VERSION 5.7 ;
  NOWIREEXTENSIONATPIN ON ;
  DIVIDERCHAR "/" ;
  BUSBITCHARS "[]" ;
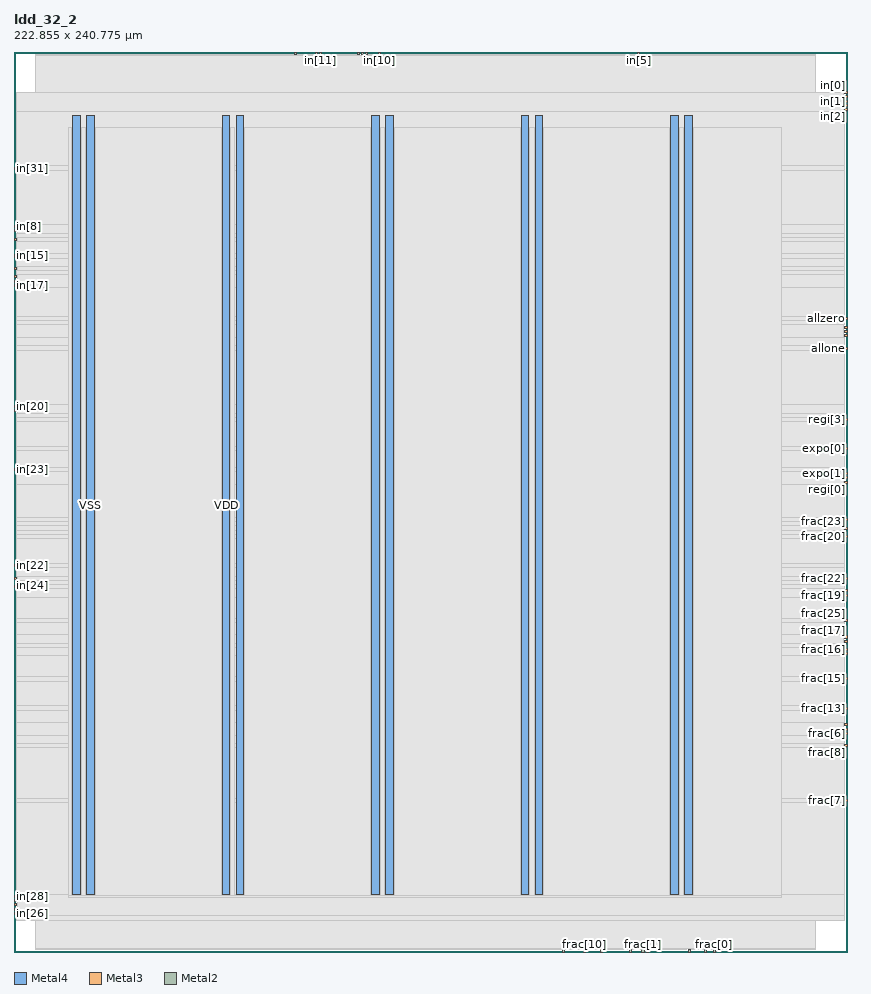
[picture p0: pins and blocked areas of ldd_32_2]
MACRO ldd_32_2
  CLASS BLOCK ;
  FOREIGN ldd_32_2 ;
  ORIGIN 0.000 0.000 ;
  SIZE 222.855 BY 240.775 ;
  PIN VDD
    DIRECTION INOUT ;
    USE POWER ;
    PORT
      LAYER Metal4 ;
        RECT 15.720 15.380 17.720 223.740 ;
    END
    PORT
      LAYER Metal4 ;
        RECT 55.720 15.380 57.720 223.740 ;
    END
    PORT
      LAYER Metal4 ;
        RECT 95.720 15.380 97.720 223.740 ;
    END
    PORT
      LAYER Metal4 ;
        RECT 135.720 15.380 137.720 223.740 ;
    END
    PORT
      LAYER Metal4 ;
        RECT 175.720 15.380 177.720 223.740 ;
    END
  END VDD
  PIN VSS
    DIRECTION INOUT ;
    USE GROUND ;
    PORT
      LAYER Metal4 ;
        RECT 19.420 15.380 21.420 223.740 ;
    END
    PORT
      LAYER Metal4 ;
        RECT 59.420 15.380 61.420 223.740 ;
    END
    PORT
      LAYER Metal4 ;
        RECT 99.420 15.380 101.420 223.740 ;
    END
    PORT
      LAYER Metal4 ;
        RECT 139.420 15.380 141.420 223.740 ;
    END
    PORT
      LAYER Metal4 ;
        RECT 179.420 15.380 181.420 223.740 ;
    END
  END VSS
  PIN allone
    DIRECTION OUTPUT ;
    USE SIGNAL ;
    ANTENNADIFFAREA 1.986000 ;
    PORT
      LAYER Metal3 ;
        RECT 222.295 161.280 222.855 161.840 ;
    END
  END allone
  PIN allzero
    DIRECTION OUTPUT ;
    USE SIGNAL ;
    ANTENNADIFFAREA 1.986000 ;
    PORT
      LAYER Metal3 ;
        RECT 222.295 169.120 222.855 169.680 ;
    END
  END allzero
  PIN expo[0]
    DIRECTION OUTPUT ;
    USE SIGNAL ;
    ANTENNADIFFAREA 1.986000 ;
    PORT
      LAYER Metal3 ;
        RECT 222.295 134.400 222.855 134.960 ;
    END
  END expo[0]
  PIN expo[1]
    DIRECTION OUTPUT ;
    USE SIGNAL ;
    ANTENNADIFFAREA 1.986000 ;
    PORT
      LAYER Metal3 ;
        RECT 222.295 127.680 222.855 128.240 ;
    END
  END expo[1]
  PIN frac[0]
    DIRECTION OUTPUT ;
    USE SIGNAL ;
    ANTENNADIFFAREA 1.986000 ;
    PORT
      LAYER Metal2 ;
        RECT 187.040 0.000 187.600 0.560 ;
    END
  END frac[0]
  PIN frac[10]
    DIRECTION OUTPUT ;
    USE SIGNAL ;
    ANTENNADIFFAREA 1.986000 ;
    PORT
      LAYER Metal2 ;
        RECT 152.320 0.000 152.880 0.560 ;
    END
  END frac[10]
  PIN frac[11]
    DIRECTION OUTPUT ;
    USE SIGNAL ;
    ANTENNADIFFAREA 1.986000 ;
    PORT
      LAYER Metal2 ;
        RECT 146.720 0.000 147.280 0.560 ;
    END
  END frac[11]
  PIN frac[12]
    DIRECTION OUTPUT ;
    USE SIGNAL ;
    ANTENNADIFFAREA 1.986000 ;
    PORT
      LAYER Metal2 ;
        RECT 156.800 0.000 157.360 0.560 ;
    END
  END frac[12]
  PIN frac[13]
    DIRECTION OUTPUT ;
    USE SIGNAL ;
    ANTENNADIFFAREA 1.986000 ;
    PORT
      LAYER Metal3 ;
        RECT 222.295 64.960 222.855 65.520 ;
    END
  END frac[13]
  PIN frac[14]
    DIRECTION OUTPUT ;
    USE SIGNAL ;
    ANTENNADIFFAREA 1.986000 ;
    PORT
      LAYER Metal3 ;
        RECT 222.295 60.480 222.855 61.040 ;
    END
  END frac[14]
  PIN frac[15]
    DIRECTION OUTPUT ;
    USE SIGNAL ;
    ANTENNADIFFAREA 1.986000 ;
    PORT
      LAYER Metal3 ;
        RECT 222.295 72.800 222.855 73.360 ;
    END
  END frac[15]
  PIN frac[16]
    DIRECTION OUTPUT ;
    USE SIGNAL ;
    ANTENNADIFFAREA 1.986000 ;
    PORT
      LAYER Metal3 ;
        RECT 222.295 80.640 222.855 81.200 ;
    END
  END frac[16]
  PIN frac[17]
    DIRECTION OUTPUT ;
    USE SIGNAL ;
    ANTENNADIFFAREA 1.986000 ;
    PORT
      LAYER Metal3 ;
        RECT 222.295 84.000 222.855 84.560 ;
    END
  END frac[17]
  PIN frac[18]
    DIRECTION OUTPUT ;
    USE SIGNAL ;
    ANTENNADIFFAREA 1.986000 ;
    PORT
      LAYER Metal3 ;
        RECT 222.295 79.520 222.855 80.080 ;
    END
  END frac[18]
  PIN frac[19]
    DIRECTION OUTPUT ;
    USE SIGNAL ;
    ANTENNADIFFAREA 1.986000 ;
    PORT
      LAYER Metal3 ;
        RECT 222.295 95.200 222.855 95.760 ;
    END
  END frac[19]
  PIN frac[1]
    DIRECTION OUTPUT ;
    USE SIGNAL ;
    ANTENNADIFFAREA 1.986000 ;
    PORT
      LAYER Metal2 ;
        RECT 168.000 0.000 168.560 0.560 ;
    END
  END frac[1]
  PIN frac[20]
    DIRECTION OUTPUT ;
    USE SIGNAL ;
    ANTENNADIFFAREA 1.986000 ;
    PORT
      LAYER Metal3 ;
        RECT 222.295 110.880 222.855 111.440 ;
    END
  END frac[20]
  PIN frac[21]
    DIRECTION OUTPUT ;
    USE SIGNAL ;
    ANTENNADIFFAREA 1.986000 ;
    PORT
      LAYER Metal3 ;
        RECT 222.295 82.880 222.855 83.440 ;
    END
  END frac[21]
  PIN frac[22]
    DIRECTION OUTPUT ;
    USE SIGNAL ;
    ANTENNADIFFAREA 1.986000 ;
    PORT
      LAYER Metal3 ;
        RECT 222.295 99.680 222.855 100.240 ;
    END
  END frac[22]
  PIN frac[23]
    DIRECTION OUTPUT ;
    USE SIGNAL ;
    ANTENNADIFFAREA 1.986000 ;
    PORT
      LAYER Metal3 ;
        RECT 222.295 113.120 222.855 113.680 ;
    END
  END frac[23]
  PIN frac[24]
    DIRECTION OUTPUT ;
    USE SIGNAL ;
    ANTENNADIFFAREA 1.986000 ;
    PORT
      LAYER Metal3 ;
        RECT 222.295 115.360 222.855 115.920 ;
    END
  END frac[24]
  PIN frac[25]
    DIRECTION OUTPUT ;
    USE SIGNAL ;
    ANTENNADIFFAREA 1.986000 ;
    PORT
      LAYER Metal3 ;
        RECT 222.295 88.480 222.855 89.040 ;
    END
  END frac[25]
  PIN frac[26]
    DIRECTION OUTPUT ;
    USE SIGNAL ;
    ANTENNADIFFAREA 1.986000 ;
    PORT
      LAYER Metal3 ;
        RECT 222.295 96.320 222.855 96.880 ;
    END
  END frac[26]
  PIN frac[2]
    DIRECTION OUTPUT ;
    USE SIGNAL ;
    ANTENNADIFFAREA 1.986000 ;
    PORT
      LAYER Metal2 ;
        RECT 164.640 0.000 165.200 0.560 ;
    END
  END frac[2]
  PIN frac[3]
    DIRECTION OUTPUT ;
    USE SIGNAL ;
    ANTENNADIFFAREA 1.986000 ;
    PORT
      LAYER Metal2 ;
        RECT 184.800 0.000 185.360 0.560 ;
    END
  END frac[3]
  PIN frac[4]
    DIRECTION OUTPUT ;
    USE SIGNAL ;
    ANTENNADIFFAREA 1.986000 ;
    PORT
      LAYER Metal2 ;
        RECT 180.320 0.000 180.880 0.560 ;
    END
  END frac[4]
  PIN frac[5]
    DIRECTION OUTPUT ;
    USE SIGNAL ;
    ANTENNADIFFAREA 1.986000 ;
    PORT
      LAYER Metal3 ;
        RECT 222.295 59.360 222.855 59.920 ;
    END
  END frac[5]
  PIN frac[6]
    DIRECTION OUTPUT ;
    USE SIGNAL ;
    ANTENNADIFFAREA 1.986000 ;
    PORT
      LAYER Metal3 ;
        RECT 222.295 58.240 222.855 58.800 ;
    END
  END frac[6]
  PIN frac[7]
    DIRECTION OUTPUT ;
    USE SIGNAL ;
    ANTENNADIFFAREA 1.986000 ;
    PORT
      LAYER Metal3 ;
        RECT 222.295 40.320 222.855 40.880 ;
    END
  END frac[7]
  PIN frac[8]
    DIRECTION OUTPUT ;
    USE SIGNAL ;
    ANTENNADIFFAREA 1.986000 ;
    PORT
      LAYER Metal3 ;
        RECT 222.295 54.880 222.855 55.440 ;
    END
  END frac[8]
  PIN frac[9]
    DIRECTION OUTPUT ;
    USE SIGNAL ;
    ANTENNADIFFAREA 1.986000 ;
    PORT
      LAYER Metal2 ;
        RECT 169.120 0.000 169.680 0.560 ;
    END
  END frac[9]
  PIN in[0]
    DIRECTION INPUT ;
    USE SIGNAL ;
    ANTENNAGATEAREA 0.498500 ;
    PORT
      LAYER Metal3 ;
        RECT 222.295 229.600 222.855 230.160 ;
    END
  END in[0]
  PIN in[10]
    DIRECTION INPUT ;
    USE SIGNAL ;
    ANTENNAGATEAREA 0.726000 ;
    PORT
      LAYER Metal2 ;
        RECT 97.440 240.215 98.000 240.775 ;
    END
  END in[10]
  PIN in[11]
    DIRECTION INPUT ;
    USE SIGNAL ;
    ANTENNAGATEAREA 1.102000 ;
    PORT
      LAYER Metal2 ;
        RECT 81.760 240.215 82.320 240.775 ;
    END
  END in[11]
  PIN in[12]
    DIRECTION INPUT ;
    USE SIGNAL ;
    ANTENNAGATEAREA 1.102000 ;
    PORT
      LAYER Metal2 ;
        RECT 80.640 240.215 81.200 240.775 ;
    END
  END in[12]
  PIN in[13]
    DIRECTION INPUT ;
    USE SIGNAL ;
    ANTENNAGATEAREA 1.102000 ;
    PORT
      LAYER Metal2 ;
        RECT 91.840 240.215 92.400 240.775 ;
    END
  END in[13]
  PIN in[14]
    DIRECTION INPUT ;
    USE SIGNAL ;
    ANTENNAGATEAREA 0.726000 ;
    PORT
      LAYER Metal2 ;
        RECT 75.040 240.215 75.600 240.775 ;
    END
  END in[14]
  PIN in[15]
    DIRECTION INPUT ;
    USE SIGNAL ;
    ANTENNAGATEAREA 0.498500 ;
    PORT
      LAYER Metal3 ;
        RECT 0.000 185.920 0.560 186.480 ;
    END
  END in[15]
  PIN in[16]
    DIRECTION INPUT ;
    USE SIGNAL ;
    ANTENNAGATEAREA 1.102000 ;
    PORT
      LAYER Metal3 ;
        RECT 0.000 182.560 0.560 183.120 ;
    END
  END in[16]
  PIN in[17]
    DIRECTION INPUT ;
    USE SIGNAL ;
    ANTENNAGATEAREA 0.498500 ;
    PORT
      LAYER Metal3 ;
        RECT 0.000 178.080 0.560 178.640 ;
    END
  END in[17]
  PIN in[18]
    DIRECTION INPUT ;
    USE SIGNAL ;
    ANTENNAGATEAREA 0.498500 ;
    PORT
      LAYER Metal3 ;
        RECT 0.000 179.200 0.560 179.760 ;
    END
  END in[18]
  PIN in[19]
    DIRECTION INPUT ;
    USE SIGNAL ;
    ANTENNAGATEAREA 1.102000 ;
    PORT
      LAYER Metal3 ;
        RECT 0.000 180.320 0.560 180.880 ;
    END
  END in[19]
  PIN in[1]
    DIRECTION INPUT ;
    USE SIGNAL ;
    ANTENNAGATEAREA 0.726000 ;
    PORT
      LAYER Metal3 ;
        RECT 222.295 227.360 222.855 227.920 ;
    END
  END in[1]
  PIN in[20]
    DIRECTION INPUT ;
    USE SIGNAL ;
    ANTENNAGATEAREA 0.498500 ;
    PORT
      LAYER Metal3 ;
        RECT 0.000 145.600 0.560 146.160 ;
    END
  END in[20]
  PIN in[21]
    DIRECTION INPUT ;
    USE SIGNAL ;
    ANTENNAGATEAREA 0.498500 ;
    PORT
      LAYER Metal3 ;
        RECT 0.000 144.480 0.560 145.040 ;
    END
  END in[21]
  PIN in[22]
    DIRECTION INPUT ;
    USE SIGNAL ;
    ANTENNAGATEAREA 0.498500 ;
    PORT
      LAYER Metal3 ;
        RECT 0.000 103.040 0.560 103.600 ;
    END
  END in[22]
  PIN in[23]
    DIRECTION INPUT ;
    USE SIGNAL ;
    ANTENNAGATEAREA 0.498500 ;
    PORT
      LAYER Metal3 ;
        RECT 0.000 128.800 0.560 129.360 ;
    END
  END in[23]
  PIN in[24]
    DIRECTION INPUT ;
    USE SIGNAL ;
    ANTENNAGATEAREA 0.498500 ;
    PORT
      LAYER Metal3 ;
        RECT 0.000 99.680 0.560 100.240 ;
    END
  END in[24]
  PIN in[25]
    DIRECTION INPUT ;
    USE SIGNAL ;
    ANTENNAGATEAREA 0.498500 ;
    PORT
      LAYER Metal3 ;
        RECT 0.000 97.440 0.560 98.000 ;
    END
  END in[25]
  PIN in[26]
    DIRECTION INPUT ;
    USE SIGNAL ;
    ANTENNAGATEAREA 0.498500 ;
    PORT
      LAYER Metal3 ;
        RECT 0.000 10.080 0.560 10.640 ;
    END
  END in[26]
  PIN in[27]
    DIRECTION INPUT ;
    USE SIGNAL ;
    ANTENNAGATEAREA 0.498500 ;
    PORT
      LAYER Metal3 ;
        RECT 0.000 12.320 0.560 12.880 ;
    END
  END in[27]
  PIN in[28]
    DIRECTION INPUT ;
    USE SIGNAL ;
    ANTENNAGATEAREA 0.498500 ;
    PORT
      LAYER Metal3 ;
        RECT 0.000 14.560 0.560 15.120 ;
    END
  END in[28]
  PIN in[29]
    DIRECTION INPUT ;
    USE SIGNAL ;
    ANTENNAGATEAREA 0.498500 ;
    PORT
      LAYER Metal3 ;
        RECT 0.000 13.440 0.560 14.000 ;
    END
  END in[29]
  PIN in[2]
    DIRECTION INPUT ;
    USE SIGNAL ;
    ANTENNAGATEAREA 0.726000 ;
    PORT
      LAYER Metal3 ;
        RECT 222.295 225.120 222.855 225.680 ;
    END
  END in[2]
  PIN in[30]
    DIRECTION INPUT ;
    USE SIGNAL ;
    ANTENNAGATEAREA 0.498500 ;
    PORT
      LAYER Metal3 ;
        RECT 0.000 11.200 0.560 11.760 ;
    END
  END in[30]
  PIN in[31]
    DIRECTION INPUT ;
    USE SIGNAL ;
    ANTENNAGATEAREA 0.726000 ;
    PORT
      LAYER Metal3 ;
        RECT 0.000 209.440 0.560 210.000 ;
    END
  END in[31]
  PIN in[3]
    DIRECTION INPUT ;
    USE SIGNAL ;
    ANTENNAGATEAREA 0.726000 ;
    PORT
      LAYER Metal3 ;
        RECT 222.295 226.240 222.855 226.800 ;
    END
  END in[3]
  PIN in[4]
    DIRECTION INPUT ;
    USE SIGNAL ;
    ANTENNAGATEAREA 1.102000 ;
    PORT
      LAYER Metal3 ;
        RECT 222.295 228.480 222.855 229.040 ;
    END
  END in[4]
  PIN in[5]
    DIRECTION INPUT ;
    USE SIGNAL ;
    ANTENNAGATEAREA 1.102000 ;
    PORT
      LAYER Metal2 ;
        RECT 166.880 240.215 167.440 240.775 ;
    END
  END in[5]
  PIN in[6]
    DIRECTION INPUT ;
    USE SIGNAL ;
    ANTENNAGATEAREA 0.498500 ;
    PORT
      LAYER Metal2 ;
        RECT 92.960 240.215 93.520 240.775 ;
    END
  END in[6]
  PIN in[7]
    DIRECTION INPUT ;
    USE SIGNAL ;
    ANTENNAGATEAREA 1.102000 ;
    PORT
      LAYER Metal2 ;
        RECT 94.080 240.215 94.640 240.775 ;
    END
  END in[7]
  PIN in[8]
    DIRECTION INPUT ;
    USE SIGNAL ;
    ANTENNAGATEAREA 0.498500 ;
    PORT
      LAYER Metal3 ;
        RECT 0.000 193.760 0.560 194.320 ;
    END
  END in[8]
  PIN in[9]
    DIRECTION INPUT ;
    USE SIGNAL ;
    ANTENNAGATEAREA 0.498500 ;
    PORT
      LAYER Metal3 ;
        RECT 0.000 192.640 0.560 193.200 ;
    END
  END in[9]
  PIN regi[0]
    DIRECTION OUTPUT ;
    USE SIGNAL ;
    ANTENNADIFFAREA 2.365600 ;
    PORT
      LAYER Metal3 ;
        RECT 222.295 125.440 222.855 126.000 ;
    END
  END regi[0]
  PIN regi[1]
    DIRECTION OUTPUT ;
    USE SIGNAL ;
    ANTENNADIFFAREA 1.986000 ;
    PORT
      LAYER Metal3 ;
        RECT 222.295 126.560 222.855 127.120 ;
    END
  END regi[1]
  PIN regi[2]
    DIRECTION OUTPUT ;
    USE SIGNAL ;
    ANTENNADIFFAREA 1.986000 ;
    PORT
      LAYER Metal3 ;
        RECT 222.295 165.760 222.855 166.320 ;
    END
  END regi[2]
  PIN regi[3]
    DIRECTION OUTPUT ;
    USE SIGNAL ;
    ANTENNADIFFAREA 1.986000 ;
    PORT
      LAYER Metal3 ;
        RECT 222.295 142.240 222.855 142.800 ;
    END
  END regi[3]
  PIN regi[4]
    DIRECTION OUTPUT ;
    USE SIGNAL ;
    ANTENNADIFFAREA 1.986000 ;
    PORT
      LAYER Metal3 ;
        RECT 222.295 164.640 222.855 165.200 ;
    END
  END regi[4]
  PIN regi[5]
    DIRECTION OUTPUT ;
    USE SIGNAL ;
    ANTENNADIFFAREA 1.986000 ;
    PORT
      LAYER Metal3 ;
        RECT 222.295 166.880 222.855 167.440 ;
    END
  END regi[5]
  PIN sign
    DIRECTION OUTPUT ;
    USE SIGNAL ;
    ANTENNADIFFAREA 1.986000 ;
    PORT
      LAYER Metal3 ;
        RECT 0.000 190.400 0.560 190.960 ;
    END
  END sign
  OBS
      LAYER Nwell ;
        RECT 6.290 15.250 216.030 223.870 ;
      LAYER Metal1 ;
        RECT 6.720 15.380 215.600 223.740 ;
      LAYER Metal2 ;
        RECT 5.740 239.915 74.740 240.215 ;
        RECT 75.900 239.915 80.340 240.215 ;
        RECT 82.620 239.915 91.540 240.215 ;
        RECT 94.940 239.915 97.140 240.215 ;
        RECT 98.300 239.915 166.580 240.215 ;
        RECT 167.740 239.915 214.340 240.215 ;
        RECT 5.740 0.860 214.340 239.915 ;
        RECT 5.740 0.560 146.420 0.860 ;
        RECT 147.580 0.560 152.020 0.860 ;
        RECT 153.180 0.560 156.500 0.860 ;
        RECT 157.660 0.560 164.340 0.860 ;
        RECT 165.500 0.560 167.700 0.860 ;
        RECT 169.980 0.560 180.020 0.860 ;
        RECT 181.180 0.560 184.500 0.860 ;
        RECT 185.660 0.560 186.740 0.860 ;
        RECT 187.900 0.560 214.340 0.860 ;
      LAYER Metal3 ;
        RECT 0.560 224.820 221.995 230.020 ;
        RECT 0.560 210.300 222.295 224.820 ;
        RECT 0.860 209.140 222.295 210.300 ;
        RECT 0.560 194.620 222.295 209.140 ;
        RECT 0.860 192.340 222.295 194.620 ;
        RECT 0.560 191.260 222.295 192.340 ;
        RECT 0.860 190.100 222.295 191.260 ;
        RECT 0.560 186.780 222.295 190.100 ;
        RECT 0.860 185.620 222.295 186.780 ;
        RECT 0.560 183.420 222.295 185.620 ;
        RECT 0.860 182.260 222.295 183.420 ;
        RECT 0.560 181.180 222.295 182.260 ;
        RECT 0.860 177.780 222.295 181.180 ;
        RECT 0.560 169.980 222.295 177.780 ;
        RECT 0.560 168.820 221.995 169.980 ;
        RECT 0.560 167.740 222.295 168.820 ;
        RECT 0.560 164.340 221.995 167.740 ;
        RECT 0.560 162.140 222.295 164.340 ;
        RECT 0.560 160.980 221.995 162.140 ;
        RECT 0.560 146.460 222.295 160.980 ;
        RECT 0.860 144.180 222.295 146.460 ;
        RECT 0.560 143.100 222.295 144.180 ;
        RECT 0.560 141.940 221.995 143.100 ;
        RECT 0.560 135.260 222.295 141.940 ;
        RECT 0.560 134.100 221.995 135.260 ;
        RECT 0.560 129.660 222.295 134.100 ;
        RECT 0.860 128.540 222.295 129.660 ;
        RECT 0.860 128.500 221.995 128.540 ;
        RECT 0.560 125.140 221.995 128.500 ;
        RECT 0.560 116.220 222.295 125.140 ;
        RECT 0.560 115.060 221.995 116.220 ;
        RECT 0.560 113.980 222.295 115.060 ;
        RECT 0.560 112.820 221.995 113.980 ;
        RECT 0.560 111.740 222.295 112.820 ;
        RECT 0.560 110.580 221.995 111.740 ;
        RECT 0.560 103.900 222.295 110.580 ;
        RECT 0.860 102.740 222.295 103.900 ;
        RECT 0.560 100.540 222.295 102.740 ;
        RECT 0.860 99.380 221.995 100.540 ;
        RECT 0.560 98.300 222.295 99.380 ;
        RECT 0.860 97.180 222.295 98.300 ;
        RECT 0.860 97.140 221.995 97.180 ;
        RECT 0.560 94.900 221.995 97.140 ;
        RECT 0.560 89.340 222.295 94.900 ;
        RECT 0.560 88.180 221.995 89.340 ;
        RECT 0.560 84.860 222.295 88.180 ;
        RECT 0.560 82.580 221.995 84.860 ;
        RECT 0.560 81.500 222.295 82.580 ;
        RECT 0.560 79.220 221.995 81.500 ;
        RECT 0.560 73.660 222.295 79.220 ;
        RECT 0.560 72.500 221.995 73.660 ;
        RECT 0.560 65.820 222.295 72.500 ;
        RECT 0.560 64.660 221.995 65.820 ;
        RECT 0.560 61.340 222.295 64.660 ;
        RECT 0.560 57.940 221.995 61.340 ;
        RECT 0.560 55.740 222.295 57.940 ;
        RECT 0.560 54.580 221.995 55.740 ;
        RECT 0.560 41.180 222.295 54.580 ;
        RECT 0.560 40.020 221.995 41.180 ;
        RECT 0.560 15.420 222.295 40.020 ;
        RECT 0.860 9.780 222.295 15.420 ;
        RECT 0.560 8.540 222.295 9.780 ;
      LAYER Metal4 ;
        RECT 14.700 15.080 15.420 220.550 ;
        RECT 18.020 15.080 19.120 220.550 ;
        RECT 21.720 15.080 55.420 220.550 ;
        RECT 58.020 15.080 59.120 220.550 ;
        RECT 61.720 15.080 95.420 220.550 ;
        RECT 98.020 15.080 99.120 220.550 ;
        RECT 101.720 15.080 135.420 220.550 ;
        RECT 138.020 15.080 139.120 220.550 ;
        RECT 141.720 15.080 175.420 220.550 ;
        RECT 178.020 15.080 179.120 220.550 ;
        RECT 181.720 15.080 205.380 220.550 ;
        RECT 14.700 14.650 205.380 15.080 ;
  END
END ldd_32_2
END LIBRARY

